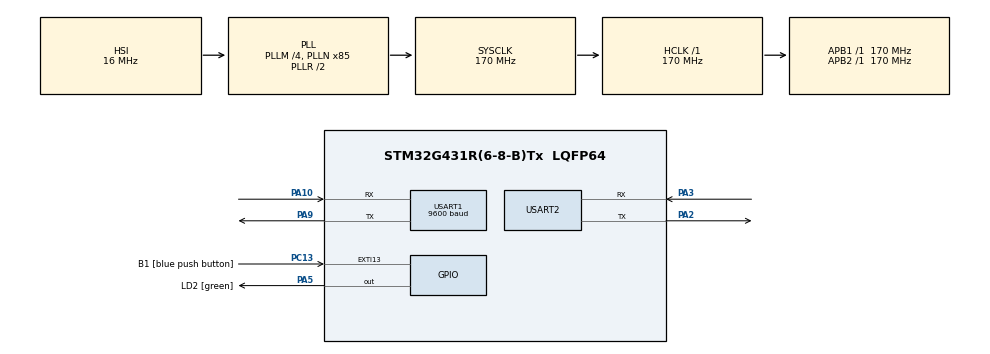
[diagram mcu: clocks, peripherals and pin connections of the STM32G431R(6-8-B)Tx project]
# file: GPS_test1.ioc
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Mcu.Family=STM32G4
Mcu.Name=STM32G431R(6-8-B)Tx
Mcu.Package=LQFP64
NVIC.PriorityGroup=NVIC_PRIORITYGROUP_4
NVIC.USART1_IRQn=true\:0\:0\:false\:false\:true\:true\:true\:true
NVIC.USART2_IRQn=true\:0\:0\:false\:false\:true\:true\:true\:true
PA10.Mode=Asynchronous
PA10.Signal=USART1_RX
PA13.GPIO_Label=T_SWDIO
PA13.Mode=Serial_Wire
PA13.Signal=SYS_JTMS-SWDIO
PA14.GPIO_Label=T_SWCLK
PA14.Mode=Serial_Wire
PA14.Signal=SYS_JTCK-SWCLK
PA2.Mode=Asynchronous
PA2.Signal=USART2_TX
PA3.Mode=Asynchronous
PA3.Signal=USART2_RX
PA5.GPIO_Label=LD2 [green]
PA5.Signal=GPIO_Output
PA9.Mode=Asynchronous
PA9.Signal=USART1_TX
PC13.GPIO_Label=B1 [blue push button]
PC13.Signal=GPXTI13
PC14-OSC32_IN.Mode=LSE-External-Oscillator
PC14-OSC32_IN.Signal=RCC_OSC32_IN
PC15-OSC32_OUT.Mode=LSE-External-Oscillator
PC15-OSC32_OUT.Signal=RCC_OSC32_OUT
PF0-OSC_IN.Mode=HSE-External-Oscillator
PF0-OSC_IN.Signal=RCC_OSC_IN
PF1-OSC_OUT.Mode=HSE-External-Oscillator
PF1-OSC_OUT.Signal=RCC_OSC_OUT
ProjectManager.HeapSize=0x200
ProjectManager.StackSize=0x400
ProjectManager.TargetToolchain=STM32CubeIDE
RCC.ADC12Freq_Value=170000000
RCC.AHBFreq_Value=170000000
RCC.APB1Freq_Value=170000000
RCC.APB1TimFreq_Value=170000000
RCC.APB2Freq_Value=170000000
RCC.APB2TimFreq_Value=170000000
RCC.CortexFreq_Value=170000000
RCC.EXTERNAL_CLOCK_VALUE=12288000
RCC.HCLKFreq_Value=170000000
RCC.HSE_VALUE=24000000
RCC.HSI48_VALUE=48000000
RCC.HSI_VALUE=16000000
RCC.PLLM=RCC_PLLM_DIV4
RCC.PLLN=85
RCC.RTCClockSelection=RCC_RTCCLKSOURCE_LSE
RCC.SYSCLKFreq_VALUE=170000000
RCC.SYSCLKSource=RCC_SYSCLKSOURCE_PLLCLK
RCC.USBFreq_Value=170000000
RCC.VCOOutputFreq_Value=340000000
USART1.BaudRate=9600
USART1.VirtualMode-Asynchronous=VM_ASYNC
USART2.VirtualMode-Asynchronous=VM_ASYNC
VP_SYS_VS_DBSignals.Mode=DisableDeadBatterySignals
board=NUCLEO-G431RB

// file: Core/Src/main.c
/* USER CODE BEGIN Header */
/**
 ******************************************************************************
 * @file           : main.c
 * @brief          : Main program body
 ******************************************************************************
 * @attention
 *
 * Copyright (c) 2022 STMicroelectronics.
 * All rights reserved.
 *
 * This software is licensed under terms that can be found in the LICENSE file
 * in the root directory of this software component.
 * If no LICENSE file comes with this software, it is provided AS-IS.
 *
 ******************************************************************************
 */
/* USER CODE END Header */
#include "main.h"

/* USER CODE BEGIN PD */
#define GPS_TRAME_SIZE 1000
/* USER CODE END PD */

UART_HandleTypeDef huart1;
UART_HandleTypeDef huart2;

/* USER CODE BEGIN PV */
char uart_gps_rx[1];
char uart_pc_tx[1];
uint8_t it_rx_gps=0;
int i = 0;
char coordonnees[GPS_TRAME_SIZE];
const char OK[]="OK*35";
char longitude_data[10];
char latitude_data[10];
char position[23];
char lat2[2];
char lat7[7];
char long3[3];
char long7[7];
double lata;
double latb;
double latitude;
double longitude;
int first_data = 0;
int data_rdy = 0;
char uart_tx_buffer[128];

double latENSEA = 49.0389554;
double longiENSEA = 2.0712599;
double DistanceMilesCarre;
double DistanceCarre;

/* USER CODE END PV */

void SystemClock_Config(void);
static void MX_GPIO_Init(void);
static void MX_USART1_UART_Init(void);
static void MX_USART2_UART_Init(void);

/* USER CODE BEGIN 0 */

//lat  49.039566040039062
//long 2.0719516277313232

void Perimetre(void){

	DistanceMilesCarre = (((latENSEA - latitude)*(latENSEA - latitude)) + ((longiENSEA - longitude)*(longiENSEA - longitude))); //Distance en miles nautiques au carré pour ne pas avoir à calculer de racine carrée
	DistanceCarre = (DistanceMilesCarre/3.429904); //Conversion de mile nautique à Km

	if(DistanceCarre >= 0.0000012){ //Si le porteur du badge se déplace à plus de ... distance
		//Distance choisie pour déclencher le "if" si on part à la distance de l'arrêt de bus.
		HAL_UART_Transmit(&huart2, uart_tx_buffer, strlen(uart_tx_buffer), HAL_MAX_DELAY);
		sprintf(uart_tx_buffer,"Je suis perdu, venez me chercher. Je suis en lat : %lf, long : %lf \r\n", latitude, longitude);

	}
}

/* USER CODE END 0 */

int main(void)
{

  /* MCU Configuration--------------------------------------------------------*/

  /* Reset of all peripherals, Initializes the Flash interface and the Systick. */
  HAL_Init();

  /* Configure the system clock */
  SystemClock_Config();

  /* Initialize all configured peripherals */
  MX_GPIO_Init();
  MX_USART1_UART_Init();
  MX_USART2_UART_Init();
  /* USER CODE BEGIN 2 */
  HAL_UART_Receive_IT(&huart1, uart_gps_rx, 1);

  /* USER CODE END 2 */

  /* Infinite loop */
	while (1)
	{

    /* USER CODE BEGIN 3 */

		//Partie "Extraction des coordonnees de la trame que le GPS nous envoie

		if(it_rx_gps){
			if(data_rdy == 1){
				for(int j = 0; j<=23;j++){
					position[j] = coordonnees[j+18]; //position[] comprend la latitude et la longitude telles que sur la trame reçue
					//En effet, les coordonnes sont d'abord de cette forme : "$GNGGA,121933.000,4902.36627,N,00204.31287,E,1,05,13.3,0.0,M,0.0,M,,*4D"
					//On sélectionne donc la partie qui est après l'identifieur et l'heure mais avant le ",E,".
				}

				for(int k = 0; k<=9;k++){
					latitude_data[k] = position[k]; //latitude non convertie
				}
				for(int l = 0; l<=10;l++){
					longitude_data[l] = position[l+13]; //longitude non convertie
				}

				lat2[0] = latitude_data[0];
				lat2[1] = latitude_data[1]; //lat2 -> les deux digits avant la virgue du degré de la lat.

				for(int m = 0; m<=6;m++){
					lat7[m] = latitude_data[m+2]; //lat 7 -> ce qui reste après la virgule de la lat.
				}

				long3[0] = longitude_data[0];
				long3[1] = longitude_data[1];
				long3[2] = longitude_data[2]; //long3 -> les trois digits avant la virgule du degré de la long.

				for(int n = 0; n<=6;n++){
					long7[n] = longitude_data[n+3]; //long7 -> ce qui reste après la virgule de la long.
				}

				float deg_lat = atof(lat2);
				float reste_lat = atof(lat7); //conversion du char[lat] en float[lat]

				float deg_long = atof(long3);
				float reste_long = atof(long7); //conversion du char[long] en float[long]

				latitude = deg_lat + (reste_lat/60); //latitude convertie
				longitude = deg_long + (reste_long/60); //longitude convertie

				HAL_UART_Transmit(&huart2, uart_tx_buffer, strlen(uart_tx_buffer), HAL_MAX_DELAY);
				sprintf(uart_tx_buffer,"latitude : %lf,\r\n longitude : %lf \r\n", latitude, longitude);
				//Nous a permis de voir si les variables latitude et longitude fonctionnaient bien lorsqu'on se déplaçait dehors.

				Perimetre(); // Permet de savoir si on est toujours dans le perimetre autorisé ou pas.

				data_rdy = 0;

			}
			if(uart_gps_rx[0]==10){
				HAL_UART_Transmit(&huart2, "\r\n", 2, HAL_MAX_DELAY); //Arrangement de la trame
			}
			else{
				uart_pc_tx[0]=uart_gps_rx[0];
				HAL_UART_Transmit(&huart2, uart_pc_tx, 1, HAL_MAX_DELAY);
				coordonnees[i] = uart_pc_tx[0]; //On copie ce qui passe dans l'UART dans un tableau coordonnees[i].
				if(i >= 4){
					if(strncmp("OK*35",&coordonnees[i-4],5) == 0){
						i = 0; //Si on trouve "OK", on réinitialise i à 0 pour synchroniser notre trame.
						if(first_data == 1){
							data_rdy = 1; //Si la trame est initialisée, le premier caractère du tableau voulu est prêt.
						}
						else first_data = 1; //Permet d'enregistrer le tableau désiré.
					}
					else{
						if(i == GPS_TRAME_SIZE-1){
							i = 0;
						}
						else{
							i++;
						}

					}

				}
				else i++;
			}

			it_rx_gps = 0;
		}

	}
  /* USER CODE END 3 */
}

void SystemClock_Config(void)
{
  RCC_OscInitTypeDef RCC_OscInitStruct = {0};
  RCC_ClkInitTypeDef RCC_ClkInitStruct = {0};

  /** Configure the main internal regulator output voltage
  */
  HAL_PWREx_ControlVoltageScaling(PWR_REGULATOR_VOLTAGE_SCALE1_BOOST);

  /** Initializes the RCC Oscillators according to the specified parameters
  * in the RCC_OscInitTypeDef structure.
  */
  RCC_OscInitStruct.OscillatorType = RCC_OSCILLATORTYPE_HSI;
  RCC_OscInitStruct.HSIState = RCC_HSI_ON;
  RCC_OscInitStruct.HSICalibrationValue = RCC_HSICALIBRATION_DEFAULT;
  RCC_OscInitStruct.PLL.PLLState = RCC_PLL_ON;
  RCC_OscInitStruct.PLL.PLLSource = RCC_PLLSOURCE_HSI;
  RCC_OscInitStruct.PLL.PLLM = RCC_PLLM_DIV4;
  RCC_OscInitStruct.PLL.PLLN = 85;
  RCC_OscInitStruct.PLL.PLLP = RCC_PLLP_DIV2;
  RCC_OscInitStruct.PLL.PLLQ = RCC_PLLQ_DIV2;
  RCC_OscInitStruct.PLL.PLLR = RCC_PLLR_DIV2;
  if (HAL_RCC_OscConfig(&RCC_OscInitStruct) != HAL_OK)
  {
    Error_Handler();
  }

  /** Initializes the CPU, AHB and APB buses clocks
  */
  RCC_ClkInitStruct.ClockType = RCC_CLOCKTYPE_HCLK|RCC_CLOCKTYPE_SYSCLK
                              |RCC_CLOCKTYPE_PCLK1|RCC_CLOCKTYPE_PCLK2;
  RCC_ClkInitStruct.SYSCLKSource = RCC_SYSCLKSOURCE_PLLCLK;
  RCC_ClkInitStruct.AHBCLKDivider = RCC_SYSCLK_DIV1;
  RCC_ClkInitStruct.APB1CLKDivider = RCC_HCLK_DIV1;
  RCC_ClkInitStruct.APB2CLKDivider = RCC_HCLK_DIV1;

  if (HAL_RCC_ClockConfig(&RCC_ClkInitStruct, FLASH_LATENCY_4) != HAL_OK)
  {
    Error_Handler();
  }
}

static void MX_USART1_UART_Init(void)
{

  huart1.Instance = USART1;
  huart1.Init.BaudRate = 9600;
  huart1.Init.WordLength = UART_WORDLENGTH_8B;
  huart1.Init.StopBits = UART_STOPBITS_1;
  huart1.Init.Parity = UART_PARITY_NONE;
  huart1.Init.Mode = UART_MODE_TX_RX;
  huart1.Init.HwFlowCtl = UART_HWCONTROL_NONE;
  huart1.Init.OverSampling = UART_OVERSAMPLING_16;
  huart1.Init.OneBitSampling = UART_ONE_BIT_SAMPLE_DISABLE;
  huart1.Init.ClockPrescaler = UART_PRESCALER_DIV1;
  huart1.AdvancedInit.AdvFeatureInit = UART_ADVFEATURE_NO_INIT;
  if (HAL_UART_Init(&huart1) != HAL_OK)
  {
    Error_Handler();
  }
  if (HAL_UARTEx_SetTxFifoThreshold(&huart1, UART_TXFIFO_THRESHOLD_1_8) != HAL_OK)
  {
    Error_Handler();
  }
  if (HAL_UARTEx_SetRxFifoThreshold(&huart1, UART_RXFIFO_THRESHOLD_1_8) != HAL_OK)
  {
    Error_Handler();
  }
  if (HAL_UARTEx_DisableFifoMode(&huart1) != HAL_OK)
  {
    Error_Handler();
  }

}

static void MX_USART2_UART_Init(void)
{

  huart2.Instance = USART2;
  huart2.Init.BaudRate = 115200;
  huart2.Init.WordLength = UART_WORDLENGTH_8B;
  huart2.Init.StopBits = UART_STOPBITS_1;
  huart2.Init.Parity = UART_PARITY_NONE;
  huart2.Init.Mode = UART_MODE_TX_RX;
  huart2.Init.HwFlowCtl = UART_HWCONTROL_NONE;
  huart2.Init.OverSampling = UART_OVERSAMPLING_16;
  huart2.Init.OneBitSampling = UART_ONE_BIT_SAMPLE_DISABLE;
  huart2.Init.ClockPrescaler = UART_PRESCALER_DIV1;
  huart2.AdvancedInit.AdvFeatureInit = UART_ADVFEATURE_NO_INIT;
  if (HAL_UART_Init(&huart2) != HAL_OK)
  {
    Error_Handler();
  }
  if (HAL_UARTEx_SetTxFifoThreshold(&huart2, UART_TXFIFO_THRESHOLD_1_8) != HAL_OK)
  {
    Error_Handler();
  }
  if (HAL_UARTEx_SetRxFifoThreshold(&huart2, UART_RXFIFO_THRESHOLD_1_8) != HAL_OK)
  {
    Error_Handler();
  }
  if (HAL_UARTEx_DisableFifoMode(&huart2) != HAL_OK)
  {
    Error_Handler();
  }

}

static void MX_GPIO_Init(void)
{
  GPIO_InitTypeDef GPIO_InitStruct = {0};

  /* GPIO Ports Clock Enable */
  __HAL_RCC_GPIOC_CLK_ENABLE();
  __HAL_RCC_GPIOF_CLK_ENABLE();
  __HAL_RCC_GPIOA_CLK_ENABLE();
  __HAL_RCC_GPIOB_CLK_ENABLE();

  /*Configure GPIO pin Output Level */
  HAL_GPIO_WritePin(LD2_GPIO_Port, LD2_Pin, GPIO_PIN_RESET);

  /*Configure GPIO pin : B1_Pin */
  GPIO_InitStruct.Pin = B1_Pin;
  GPIO_InitStruct.Mode = GPIO_MODE_IT_RISING;
  GPIO_InitStruct.Pull = GPIO_NOPULL;
  HAL_GPIO_Init(B1_GPIO_Port, &GPIO_InitStruct);

  /*Configure GPIO pins : LPUART1_TX_Pin LPUART1_RX_Pin */
  GPIO_InitStruct.Pin = LPUART1_TX_Pin|LPUART1_RX_Pin;
  GPIO_InitStruct.Mode = GPIO_MODE_AF_PP;
  GPIO_InitStruct.Pull = GPIO_NOPULL;
  GPIO_InitStruct.Speed = GPIO_SPEED_FREQ_LOW;
  GPIO_InitStruct.Alternate = GPIO_AF12_LPUART1;
  HAL_GPIO_Init(GPIOA, &GPIO_InitStruct);

  /*Configure GPIO pin : LD2_Pin */
  GPIO_InitStruct.Pin = LD2_Pin;
  GPIO_InitStruct.Mode = GPIO_MODE_OUTPUT_PP;
  GPIO_InitStruct.Pull = GPIO_NOPULL;
  GPIO_InitStruct.Speed = GPIO_SPEED_FREQ_LOW;
  HAL_GPIO_Init(LD2_GPIO_Port, &GPIO_InitStruct);

}

/* USER CODE BEGIN 4 */
void HAL_UART_RxCpltCallback(UART_HandleTypeDef *huart){
	it_rx_gps = 1;
	HAL_UART_Receive_IT(&huart1, uart_gps_rx, 1);
}

/* USER CODE END 4 */

void Error_Handler(void)
{
	__disable_irq();
	while (1)
	{
	}
}
